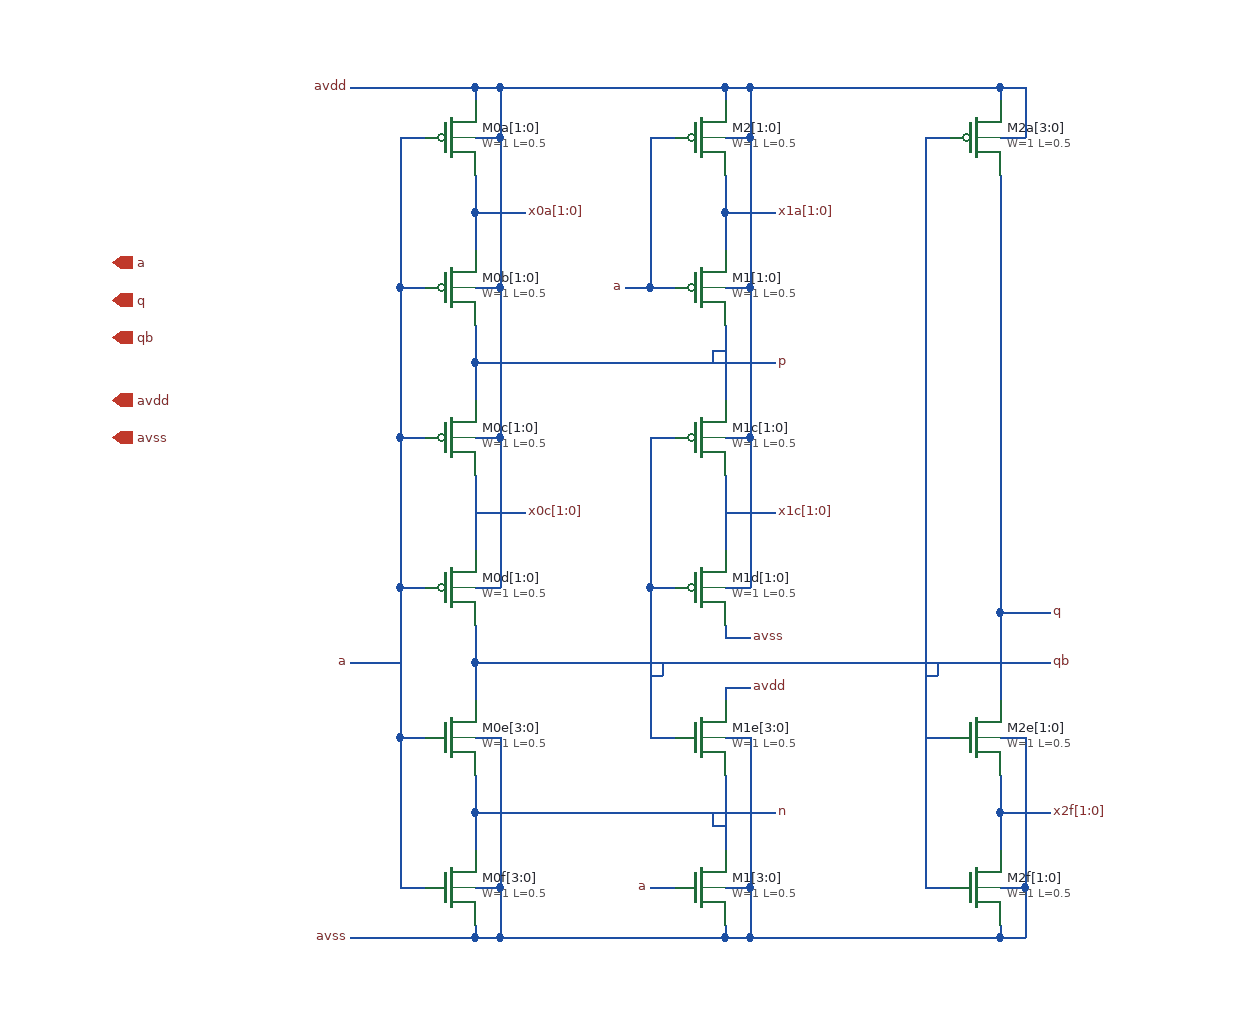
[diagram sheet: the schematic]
v {xschem version=2.9.9 file_version=1.2 }
G {}
K {}
V {}
S {}
E {}
N 340 -230 340 -200 { lab=n}
N 340 -200 340 -170 { lab=n}
N 280 -140 300 -140 { lab=a}
N 280 -260 280 -140 { lab=a}
N 280 -260 300 -260 { lab=a}
N 340 -260 360 -260 { lab=avss}
N 360 -260 360 -140 { lab=avss}
N 340 -140 360 -140 { lab=avss}
N 360 -140 360 -100 { lab=avss}
N 340 -100 360 -100 { lab=avss}
N 340 -110 340 -100 { lab=avss}
N 540 -260 560 -260 { lab=avss}
N 340 -320 340 -290 { lab=qb}
N 340 -350 340 -320 { lab=qb}
N 480 -260 500 -260 { lab=qb}
N 340 -470 340 -410 { lab=x0c[1:0]}
N 280 -380 300 -380 { lab=a}
N 280 -500 280 -380 { lab=a}
N 280 -500 300 -500 { lab=a}
N 280 -620 280 -500 { lab=a}
N 280 -620 300 -620 { lab=a}
N 280 -740 280 -620 { lab=a}
N 280 -740 300 -740 { lab=a}
N 340 -560 340 -530 { lab=p}
N 340 -590 340 -560 { lab=p}
N 340 -680 340 -650 { lab=x0a[1:0]}
N 340 -710 340 -680 { lab=x0a[1:0]}
N 340 -780 340 -770 { lab=avdd}
N 540 -470 540 -410 { lab=x1c[1:0]}
N 480 -380 500 -380 { lab=qb}
N 480 -500 480 -380 { lab=qb}
N 480 -500 500 -500 { lab=qb}
N 340 -380 360 -380 { lab=avdd}
N 360 -500 360 -380 { lab=avdd}
N 340 -500 360 -500 { lab=avdd}
N 360 -620 360 -500 { lab=avdd}
N 340 -620 360 -620 { lab=avdd}
N 360 -740 360 -620 { lab=avdd}
N 340 -740 360 -740 { lab=avdd}
N 360 -780 360 -740 { lab=avdd}
N 340 -780 360 -780 { lab=avdd}
N 540 -380 560 -380 { lab=avdd}
N 560 -500 560 -380 { lab=avdd}
N 540 -500 560 -500 { lab=avdd}
N 540 -350 540 -340 { lab=avss}
N 540 -300 540 -290 { lab=avdd}
N 480 -380 480 -260 { lab=qb}
N 280 -380 280 -260 { lab=a}
N 700 -740 720 -740 { lab=qb}
N 760 -780 760 -770 { lab=avdd}
N 760 -740 780 -740 { lab=avdd}
N 780 -780 780 -740 { lab=avdd}
N 760 -780 780 -780 { lab=avdd}
N 700 -140 720 -140 { lab=qb}
N 760 -140 780 -140 { lab=avss}
N 780 -140 780 -100 { lab=avss}
N 760 -100 780 -100 { lab=avss}
N 760 -110 760 -100 { lab=avss}
N 700 -740 700 -140 { lab=qb}
N 700 -260 720 -260 { lab=qb}
N 760 -260 780 -260 { lab=avss}
N 240 -320 280 -320 { lab=a}
N 240 -780 340 -780 { lab=avdd}
N 240 -100 340 -100 { lab=avss}
N 340 -320 800 -320 { lab=qb}
N 540 -340 560 -340 { lab=avss}
N 540 -300 560 -300 { lab=avdd}
N 490 -320 490 -310 { lab=qb}
N 480 -310 490 -310 { lab=qb}
N 710 -320 710 -310 { lab=qb}
N 700 -310 710 -310 { lab=qb}
N 760 -360 800 -360 { lab=qb}
N 760 -200 760 -170 { lab=x2f[1:0]}
N 760 -230 760 -200 { lab=x2f[1:0]}
N 780 -260 780 -140 { lab=avss}
N 760 -360 760 -290 { lab=qb}
N 760 -710 760 -360 { lab=qb}
N 760 -200 800 -200 { lab=x2f[1:0]}
N 340 -440 380 -440 { lab=x0c[1:0]}
N 340 -680 380 -680 { lab=x0a[1:0]}
N 540 -440 580 -440 { lab=x1c[1:0]}
N 480 -620 500 -620 { lab=a}
N 480 -740 480 -620 { lab=a}
N 480 -740 500 -740 { lab=a}
N 540 -680 540 -650 { lab=x1a[1:0]}
N 540 -710 540 -680 { lab=x1a[1:0]}
N 540 -780 540 -770 { lab=avdd}
N 540 -620 560 -620 { lab=avdd}
N 560 -740 560 -620 { lab=avdd}
N 540 -740 560 -740 { lab=avdd}
N 560 -780 560 -740 { lab=avdd}
N 540 -780 560 -780 { lab=avdd}
N 540 -680 580 -680 { lab=x1a[1:0]}
N 540 -590 540 -530 { lab=p}
N 360 -780 540 -780 { lab=avdd}
N 560 -780 760 -780 { lab=avdd}
N 560 -620 560 -500 { lab=avdd}
N 340 -560 580 -560 { lab=p}
N 530 -570 540 -570 { lab=p}
N 530 -570 530 -560 { lab=p}
N 480 -140 500 -140 { lab=a}
N 540 -140 560 -140 { lab=avss}
N 560 -140 560 -100 { lab=avss}
N 540 -100 560 -100 { lab=avss}
N 540 -110 540 -100 { lab=avss}
N 360 -100 540 -100 { lab=avss}
N 560 -100 760 -100 { lab=avss}
N 540 -230 540 -170 { lab=n}
N 530 -200 530 -190 { lab=n}
N 530 -190 540 -190 { lab=n}
N 560 -260 560 -140 { lab=avss}
N 460 -620 480 -620 { lab=a}
N 340 -200 580 -200 { lab=n}
C {devices/title.sym} 160 -40 0 0 {name=l6 author="Luis Henrique Rodovalho"}
C {devices/iopin.sym} 50 -530 2 1 {name=pavdd lab=avdd}
C {devices/iopin.sym} 50 -500 2 1 {name=pavss lab=avss}
C {devices/iopin.sym} 50 -640 2 1 {name=pa lab=a}
C {devices/iopin.sym} 50 -610 2 1 {name=pz lab=q}
C {sky130_fd_pr/pfet_g5v0d10v5.sym} 320 -380 0 0 {name=M0d[1:0]
L=0.5
W=1
nf=1
mult=1
ad="'int((nf+1)/2) * W/nf * 0.29'" 
pd="'2*int((nf+1)/2) * (W/nf + 0.29)'"
as="'int((nf+2)/2) * W/nf * 0.29'" 
ps="'2*int((nf+2)/2) * (W/nf + 0.29)'"
nrd="'0.29 / W'" nrs="'0.29 / W'"
sa=0 sb=0 sd=0
model=pfet_g5v0d10v5
spiceprefix=X
}
C {sky130_fd_pr/pfet_g5v0d10v5.sym} 320 -500 0 0 {name=M0c[1:0]
L=0.5
W=1
nf=1
mult=1
ad="'int((nf+1)/2) * W/nf * 0.29'" 
pd="'2*int((nf+1)/2) * (W/nf + 0.29)'"
as="'int((nf+2)/2) * W/nf * 0.29'" 
ps="'2*int((nf+2)/2) * (W/nf + 0.29)'"
nrd="'0.29 / W'" nrs="'0.29 / W'"
sa=0 sb=0 sd=0
model=pfet_g5v0d10v5
spiceprefix=X
}
C {sky130_fd_pr/nfet_g5v0d10v5.sym} 320 -260 0 0 {name=M0e[3:0]
L=0.5
W=1
nf=1
mult=1
ad="'int((nf+1)/2) * W/nf * 0.29'" 
pd="'2*int((nf+1)/2) * (W/nf + 0.29)'"
as="'int((nf+2)/2) * W/nf * 0.29'" 
ps="'2*int((nf+2)/2) * (W/nf + 0.29)'"
nrd="'0.29 / W'" nrs="'0.29 / W'"
sa=0 sb=0 sd=0
model=nfet_g5v0d10v5
spiceprefix=X
}
C {sky130_fd_pr/nfet_g5v0d10v5.sym} 320 -140 0 0 {name=M0f[3:0]
L=0.5
W=1
nf=1
mult=1
ad="'int((nf+1)/2) * W/nf * 0.29'" 
pd="'2*int((nf+1)/2) * (W/nf + 0.29)'"
as="'int((nf+2)/2) * W/nf * 0.29'" 
ps="'2*int((nf+2)/2) * (W/nf + 0.29)'"
nrd="'0.29 / W'" nrs="'0.29 / W'"
sa=0 sb=0 sd=0
model=nfet_g5v0d10v5
spiceprefix=X
}
C {sky130_fd_pr/pfet_g5v0d10v5.sym} 320 -620 0 0 {name=M0b[1:0]
L=0.5
W=1
nf=1
mult=1
ad="'int((nf+1)/2) * W/nf * 0.29'" 
pd="'2*int((nf+1)/2) * (W/nf + 0.29)'"
as="'int((nf+2)/2) * W/nf * 0.29'" 
ps="'2*int((nf+2)/2) * (W/nf + 0.29)'"
nrd="'0.29 / W'" nrs="'0.29 / W'"
sa=0 sb=0 sd=0
model=pfet_g5v0d10v5
spiceprefix=X
}
C {sky130_fd_pr/pfet_g5v0d10v5.sym} 320 -740 0 0 {name=M0a[1:0]
L=0.5
W=1
nf=1
mult=1
ad="'int((nf+1)/2) * W/nf * 0.29'" 
pd="'2*int((nf+1)/2) * (W/nf + 0.29)'"
as="'int((nf+2)/2) * W/nf * 0.29'" 
ps="'2*int((nf+2)/2) * (W/nf + 0.29)'"
nrd="'0.29 / W'" nrs="'0.29 / W'"
sa=0 sb=0 sd=0
model=pfet_g5v0d10v5
spiceprefix=X
}
C {sky130_fd_pr/nfet_g5v0d10v5.sym} 520 -260 0 0 {name=M1e[3:0]
L=0.5
W=1
nf=1
mult=1
ad="'int((nf+1)/2) * W/nf * 0.29'" 
pd="'2*int((nf+1)/2) * (W/nf + 0.29)'"
as="'int((nf+2)/2) * W/nf * 0.29'" 
ps="'2*int((nf+2)/2) * (W/nf + 0.29)'"
nrd="'0.29 / W'" nrs="'0.29 / W'"
sa=0 sb=0 sd=0
model=nfet_g5v0d10v5
spiceprefix=X
}
C {sky130_fd_pr/pfet_g5v0d10v5.sym} 520 -380 0 0 {name=M1d[1:0]
L=0.5
W=1
nf=1
mult=1
ad="'int((nf+1)/2) * W/nf * 0.29'" 
pd="'2*int((nf+1)/2) * (W/nf + 0.29)'"
as="'int((nf+2)/2) * W/nf * 0.29'" 
ps="'2*int((nf+2)/2) * (W/nf + 0.29)'"
nrd="'0.29 / W'" nrs="'0.29 / W'"
sa=0 sb=0 sd=0
model=pfet_g5v0d10v5
spiceprefix=X
}
C {sky130_fd_pr/pfet_g5v0d10v5.sym} 520 -500 0 0 {name=M1c[1:0]
L=0.5
W=1
nf=1
mult=1
ad="'int((nf+1)/2) * W/nf * 0.29'" 
pd="'2*int((nf+1)/2) * (W/nf + 0.29)'"
as="'int((nf+2)/2) * W/nf * 0.29'" 
ps="'2*int((nf+2)/2) * (W/nf + 0.29)'"
nrd="'0.29 / W'" nrs="'0.29 / W'"
sa=0 sb=0 sd=0
model=pfet_g5v0d10v5
spiceprefix=X
}
C {sky130_fd_pr/pfet_g5v0d10v5.sym} 740 -740 0 0 {name=M2a[3:0]
L=0.5
W=1
nf=1
mult=1
ad="'int((nf+1)/2) * W/nf * 0.29'" 
pd="'2*int((nf+1)/2) * (W/nf + 0.29)'"
as="'int((nf+2)/2) * W/nf * 0.29'" 
ps="'2*int((nf+2)/2) * (W/nf + 0.29)'"
nrd="'0.29 / W'" nrs="'0.29 / W'"
sa=0 sb=0 sd=0
model=pfet_g5v0d10v5
spiceprefix=X
}
C {sky130_fd_pr/nfet_g5v0d10v5.sym} 740 -140 0 0 {name=M2f[1:0]
L=0.5
W=1
nf=1
mult=1
ad="'int((nf+1)/2) * W/nf * 0.29'" 
pd="'2*int((nf+1)/2) * (W/nf + 0.29)'"
as="'int((nf+2)/2) * W/nf * 0.29'" 
ps="'2*int((nf+2)/2) * (W/nf + 0.29)'"
nrd="'0.29 / W'" nrs="'0.29 / W'"
sa=0 sb=0 sd=0
model=nfet_g5v0d10v5
spiceprefix=X
}
C {sky130_fd_pr/nfet_g5v0d10v5.sym} 740 -260 0 0 {name=M2e[1:0]
L=0.5
W=1
nf=1
mult=1
ad="'int((nf+1)/2) * W/nf * 0.29'" 
pd="'2*int((nf+1)/2) * (W/nf + 0.29)'"
as="'int((nf+2)/2) * W/nf * 0.29'" 
ps="'2*int((nf+2)/2) * (W/nf + 0.29)'"
nrd="'0.29 / W'" nrs="'0.29 / W'"
sa=0 sb=0 sd=0
model=nfet_g5v0d10v5
spiceprefix=X
}
C {devices/iopin.sym} 50 -580 2 1 {name=pzb lab=qb}
C {devices/lab_pin.sym} 240 -320 0 0 {name=la sig_type=std_logic lab=a}
C {devices/lab_pin.sym} 240 -780 0 0 {name=lavdd0 sig_type=std_logic lab=avdd}
C {devices/lab_pin.sym} 240 -100 0 0 {name=lavss0 sig_type=std_logic lab=avss}
C {devices/lab_pin.sym} 560 -300 0 1 {name=lavdd1 sig_type=std_logic lab=avdd}
C {devices/lab_pin.sym} 560 -340 0 1 {name=lavss1 sig_type=std_logic lab=avss}
C {devices/lab_pin.sym} 800 -320 0 1 {name=lqb3 sig_type=std_logic lab=qb}
C {devices/lab_pin.sym} 800 -360 0 1 {name=lq sig_type=std_logic lab=q}
C {devices/lab_pin.sym} 800 -200 0 1 {name=lqb1 sig_type=std_logic lab=x2f[1:0]}
C {devices/lab_pin.sym} 380 -440 0 1 {name=lqb2 sig_type=std_logic lab=x0c[1:0]}
C {devices/lab_pin.sym} 380 -680 0 1 {name=lx0a sig_type=std_logic lab=x0a[1:0]}
C {devices/lab_pin.sym} 580 -440 0 1 {name=lx1c sig_type=std_logic lab=x1c[1:0]}
C {devices/lab_pin.sym} 580 -200 0 1 {name=ln sig_type=std_logic lab=n}
C {devices/lab_pin.sym} 580 -560 0 1 {name=lp sig_type=std_logic lab=p}
C {sky130_fd_pr/pfet_g5v0d10v5.sym} 520 -620 0 0 {name=M1[1:0]
L=0.5
W=1
nf=1
mult=1
ad="'int((nf+1)/2) * W/nf * 0.29'" 
pd="'2*int((nf+1)/2) * (W/nf + 0.29)'"
as="'int((nf+2)/2) * W/nf * 0.29'" 
ps="'2*int((nf+2)/2) * (W/nf + 0.29)'"
nrd="'0.29 / W'" nrs="'0.29 / W'"
sa=0 sb=0 sd=0
model=pfet_g5v0d10v5
spiceprefix=X
}
C {sky130_fd_pr/pfet_g5v0d10v5.sym} 520 -740 0 0 {name=M2[1:0]
L=0.5
W=1
nf=1
mult=1
ad="'int((nf+1)/2) * W/nf * 0.29'" 
pd="'2*int((nf+1)/2) * (W/nf + 0.29)'"
as="'int((nf+2)/2) * W/nf * 0.29'" 
ps="'2*int((nf+2)/2) * (W/nf + 0.29)'"
nrd="'0.29 / W'" nrs="'0.29 / W'"
sa=0 sb=0 sd=0
model=pfet_g5v0d10v5
spiceprefix=X
}
C {devices/lab_pin.sym} 580 -680 0 1 {name=lx1 sig_type=std_logic lab=x1a[1:0]}
C {sky130_fd_pr/nfet_g5v0d10v5.sym} 520 -140 0 0 {name=M1[3:0]
L=0.5
W=1
nf=1
mult=1
ad="'int((nf+1)/2) * W/nf * 0.29'" 
pd="'2*int((nf+1)/2) * (W/nf + 0.29)'"
as="'int((nf+2)/2) * W/nf * 0.29'" 
ps="'2*int((nf+2)/2) * (W/nf + 0.29)'"
nrd="'0.29 / W'" nrs="'0.29 / W'"
sa=0 sb=0 sd=0
model=nfet_g5v0d10v5
spiceprefix=X
}
C {devices/lab_pin.sym} 480 -140 0 0 {name=la1 sig_type=std_logic lab=a}
C {devices/lab_pin.sym} 460 -620 0 0 {name=la2 sig_type=std_logic lab=a}
